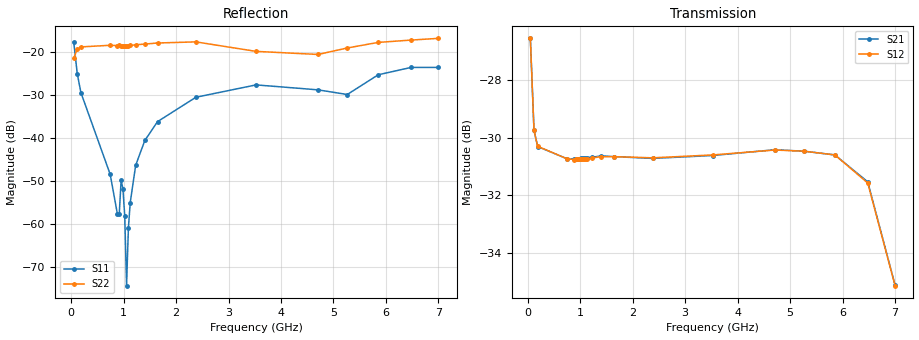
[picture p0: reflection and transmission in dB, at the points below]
! Integrated Device Technology
! Corporate Headquarters
! 6024 Silver Creek Valley Road
! San Jose, CA 95138  USA
! Phone:  1-408-284-8200
! Toll Free:  1-800-223-1366
! Webpage:  http://www.idt.com/
! Timing and RF Division
! 515 Groton Road, Suite 102
! Westford, MA 01886-6024
! Device:  F2258
! Description: Voltage Variable RF Attenuator
! Frequency:  50.0 -  6000.00 MHz
! Package:  3x3 mm Thin QFN Plastic Package: 16 pin
! Ports:  2 RF, 2 DC
!  Pin  1  = NC
!  Pin  2  = NC
!  Pin  3  = RF2  = Port 2
!  Pin  4  = GND
!  Pin  5  = Vdd
!  Pin  6  = NC
!  Pin  7  = VCTRL
!  Pin  8  = NC
!  Pin  9  = GND
!  Pin 10  = RF1  = Port 1
!  Pin 11  = NC
!  Pin 12  = NC
!  Pin 13  = NC
!  Pin 14  = NC
!  Pin 15  = NC
!  Pin 16  = NC
! Vcntrl:  1.690 Volts
! Vdd:  +3.300 Volts
! Current:  1.157 mA
! Data:  The device was measured on a the F2258 evaluation board which has
!  individual transmission lines to the RF pins.  Data was collected
!  using a calibrated network analyzer.  The evaluation board was
!  de-embedded using a TRL calibration technique.
!  The reference plane is the edge of the package pin.
! Misc:  SN 10
!  Action Tracker AT0285
! Date Measured:  2014-12-10
! Date:  2016-01-13  MJV
! Note:
!  Integrated Device Technology supplies this data as a sample of measured
!  data at the package pin for this product.  Your particular data for this
!  product may vary.
!  Data was taken at 25 degrees C.
!  Integrated Device Technology reserves the right to change this data at anytime.
!Freq_(GHz)  S11M_(dB)  S11P_(deg)  S21M_(dB)  S21P_(deg)  S12M_(dB)  S12P_(deg)  S22M_(dB)  S22P_(deg)
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# GHz S dB R 50
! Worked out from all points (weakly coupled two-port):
!   201 points, 50 MHz to 7 GHz, reference 50 ohm
!   highest |S21| = -26.57 dB at 50 MHz (marker M1); lowest = -35.1 dB at 7 GHz (marker M2)
!   lowest |S11| = -74.4 dB at 1.058 GHz (marker M3), VSWR 1.00, Z = 50 + j0.0186 ohm
!   |S11| at or under -10 dB: start of sweep to end of sweep
!   |S22| runs from -21.4 to -16.7 dB; largest |S21 - S12| = 0.0002
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0.05  -17.52 -110.1  -26.57 -52.0  -26.57 -52.0  -21.43 -48.8
0.1195  -25.10 -105.4  -29.75 -27.7  -29.75 -27.7  -19.20 -14.0
0.189  -29.43 -107.2  -30.31 -19.1  -30.30 -19.1  -18.74 -9.2
0.745  -48.40 -128.7  -30.73 -10.5  -30.73 -10.5  -18.36 -9.1
0.884  -57.75 168.9  -30.74 -10.8  -30.76 -10.8  -18.42 -10.8
0.91875  -57.61 138.6  -30.74 -10.9  -30.75 -10.9  -18.41 -11.3
0.9535  -49.82 -150.6  -30.74 -11.0  -30.75 -11.0  -18.64 -10.6
0.98825  -51.73 -162.8  -30.73 -11.1  -30.74 -11.1  -18.61 -11.4
1.023  -58.14 -174.3  -30.72 -11.2  -30.75 -11.2  -18.53 -11.8
1.05775  -74.36 103.1  -30.71 -11.3  -30.73 -11.3  -18.47 -12.0
1.0925  -60.97 56.9  -30.70 -11.5  -30.74 -11.4  -18.46 -12.4
1.12725  -55.02 53.1  -30.69 -11.6  -30.75 -11.6  -18.41 -12.8
1.2315  -46.31 32.8  -30.68 -12.2  -30.70 -12.2  -18.24 -13.8
1.40525  -40.54 27.5  -30.63 -13.5  -30.66 -13.5  -18.08 -15.1
1.6485  -36.14 28.8  -30.66 -15.4  -30.66 -15.4  -17.83 -17.7
2.37825  -30.47 45.8  -30.72 -20.9  -30.70 -20.9  -17.57 -23.7
3.525  -27.59 90.5  -30.62 -30.4  -30.60 -30.4  -19.78 -38.2
4.7065  -28.74 95.0  -30.42 -41.6  -30.43 -41.6  -20.50 -62.7
5.2625  -29.83 52.7  -30.47 -47.8  -30.47 -47.8  -18.99 -65.2
5.85325  -25.23 28.8  -30.60 -56.7  -30.60 -56.7  -17.69 -64.8
6.47875  -23.52 40.7  -31.53 -69.5  -31.57 -69.4  -17.15 -81.0
7  -23.51 83.9  -35.10 -70.5  -35.12 -70.4  -16.75 -126.1
